VERSION 5.7 ;
  NOWIREEXTENSIONATPIN ON ;
  DIVIDERCHAR "/" ;
  BUSBITCHARS "[]" ;
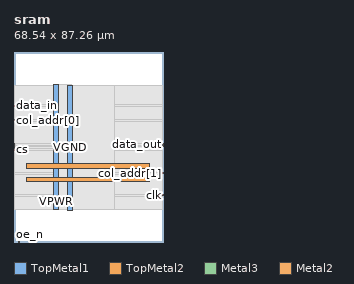
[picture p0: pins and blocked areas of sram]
MACRO sram
  CLASS BLOCK ;
  FOREIGN sram ;
  ORIGIN 0.000 0.000 ;
  SIZE 68.540 BY 87.260 ;
  PIN VGND
    DIRECTION INOUT ;
    USE GROUND ;
    PORT
      LAYER TopMetal1 ;
        RECT 24.460 14.490 26.660 72.040 ;
    END
    PORT
      LAYER TopMetal2 ;
        RECT 5.760 33.820 62.400 36.020 ;
    END
  END VGND
  PIN VPWR
    DIRECTION INOUT ;
    USE POWER ;
    PORT
      LAYER TopMetal1 ;
        RECT 18.260 14.900 20.460 72.450 ;
    END
    PORT
      LAYER TopMetal2 ;
        RECT 5.760 27.620 62.400 29.820 ;
    END
  END VPWR
  PIN clk
    DIRECTION INPUT ;
    USE SIGNAL ;
    ANTENNAGATEAREA 1.450800 ;
    PORT
      LAYER Metal3 ;
        RECT 68.140 21.220 68.540 21.620 ;
    END
  END clk
  PIN col_addr[0]
    DIRECTION INPUT ;
    USE SIGNAL ;
    ANTENNAGATEAREA 0.180700 ;
    PORT
      LAYER Metal3 ;
        RECT 0.000 55.660 0.400 56.060 ;
    END
  END col_addr[0]
  PIN col_addr[1]
    DIRECTION INPUT ;
    USE SIGNAL ;
    ANTENNAGATEAREA 0.180700 ;
    PORT
      LAYER Metal3 ;
        RECT 68.140 31.300 68.540 31.700 ;
    END
  END col_addr[1]
  PIN cs
    DIRECTION INPUT ;
    USE SIGNAL ;
    ANTENNAGATEAREA 0.180700 ;
    PORT
      LAYER Metal3 ;
        RECT 0.000 42.220 0.400 42.620 ;
    END
  END cs
  PIN data_in
    DIRECTION INPUT ;
    USE SIGNAL ;
    ANTENNAGATEAREA 0.180700 ;
    PORT
      LAYER Metal3 ;
        RECT 0.000 62.380 0.400 62.780 ;
    END
  END data_in
  PIN data_out
    DIRECTION OUTPUT ;
    USE SIGNAL ;
    ANTENNADIFFAREA 0.708600 ;
    PORT
      LAYER Metal3 ;
        RECT 68.140 44.740 68.540 45.140 ;
    END
  END data_out
  PIN data_out_bar
    DIRECTION OUTPUT ;
    USE SIGNAL ;
    ANTENNADIFFAREA 0.708600 ;
    PORT
      LAYER Metal3 ;
        RECT 68.140 43.900 68.540 44.300 ;
    END
  END data_out_bar
  PIN oe_n
    DIRECTION INPUT ;
    USE SIGNAL ;
    PORT
      LAYER Metal2 ;
        RECT 2.200 0.000 2.600 0.400 ;
    END
  END oe_n
  PIN row_addr[0]
    DIRECTION INPUT ;
    USE SIGNAL ;
    ANTENNAGATEAREA 0.180700 ;
    PORT
      LAYER Metal3 ;
        RECT 0.000 44.740 0.400 45.140 ;
    END
  END row_addr[0]
  PIN row_addr[1]
    DIRECTION INPUT ;
    USE SIGNAL ;
    ANTENNAGATEAREA 0.180700 ;
    PORT
      LAYER Metal3 ;
        RECT 0.000 43.900 0.400 44.300 ;
    END
  END row_addr[1]
  PIN we_n
    DIRECTION INPUT ;
    USE SIGNAL ;
    ANTENNAGATEAREA 0.180700 ;
    PORT
      LAYER Metal3 ;
        RECT 0.000 43.060 0.400 43.460 ;
    END
  END we_n
  OBS
      LAYER GatPoly ;
        RECT 5.760 14.970 62.400 71.970 ;
      LAYER Metal1 ;
        RECT 5.760 14.900 62.400 72.040 ;
      LAYER Metal2 ;
        RECT 6.135 14.975 62.980 71.965 ;
      LAYER Metal3 ;
        RECT 0.400 62.990 68.140 71.920 ;
        RECT 0.610 62.170 68.140 62.990 ;
        RECT 0.400 56.270 68.140 62.170 ;
        RECT 0.610 55.450 68.140 56.270 ;
        RECT 0.400 45.350 68.140 55.450 ;
        RECT 0.610 44.530 67.930 45.350 ;
        RECT 0.400 44.510 68.140 44.530 ;
        RECT 0.610 43.690 67.930 44.510 ;
        RECT 0.400 43.670 68.140 43.690 ;
        RECT 0.610 42.850 68.140 43.670 ;
        RECT 0.400 42.830 68.140 42.850 ;
        RECT 0.610 42.010 68.140 42.830 ;
        RECT 0.400 31.910 68.140 42.010 ;
        RECT 0.400 31.090 67.930 31.910 ;
        RECT 0.400 21.830 68.140 31.090 ;
        RECT 0.400 21.010 67.930 21.830 ;
        RECT 0.400 15.020 68.140 21.010 ;
      LAYER Metal4 ;
        RECT 18.440 14.975 46.180 71.965 ;
      LAYER Metal5 ;
        RECT 18.395 14.810 26.525 72.130 ;
  END
END sram
END LIBRARY

